VERSION 5.7 ;
  NOWIREEXTENSIONATPIN ON ;
  DIVIDERCHAR "/" ;
  BUSBITCHARS "[]" ;
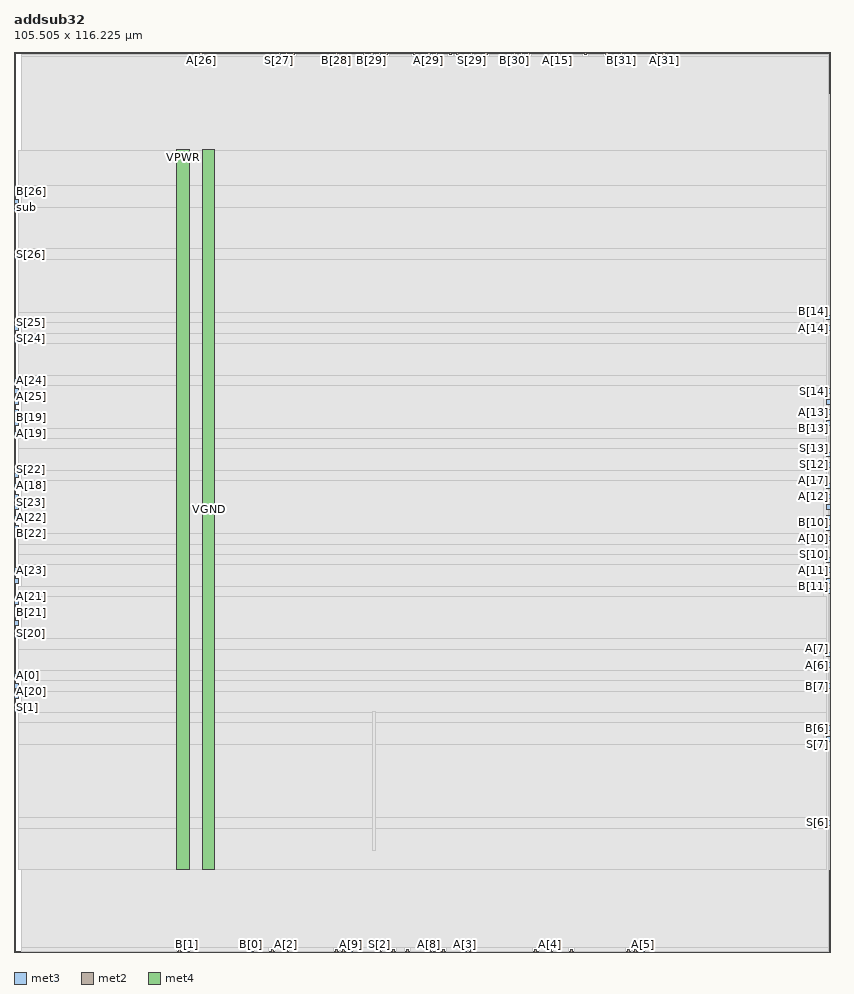
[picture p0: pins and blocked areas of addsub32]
MACRO addsub32
  CLASS BLOCK ;
  FOREIGN addsub32 ;
  ORIGIN 0.000 0.000 ;
  SIZE 105.505 BY 116.225 ;
  PIN A[0]
    DIRECTION INPUT ;
    USE SIGNAL ;
    ANTENNAGATEAREA 0.213000 ;
    PORT
      LAYER met3 ;
        RECT 0.000 35.400 0.600 36.000 ;
    END
  END A[0]
  PIN A[10]
    DIRECTION INPUT ;
    USE SIGNAL ;
    ANTENNAGATEAREA 0.213000 ;
    PORT
      LAYER met3 ;
        RECT 104.905 53.080 105.505 53.680 ;
    END
  END A[10]
  PIN A[11]
    DIRECTION INPUT ;
    USE SIGNAL ;
    ANTENNAGATEAREA 0.213000 ;
    PORT
      LAYER met3 ;
        RECT 104.905 49.000 105.505 49.600 ;
    END
  END A[11]
  PIN A[12]
    DIRECTION INPUT ;
    USE SIGNAL ;
    ANTENNAGATEAREA 0.213000 ;
    PORT
      LAYER met3 ;
        RECT 104.905 58.520 105.505 59.120 ;
    END
  END A[12]
  PIN A[13]
    DIRECTION INPUT ;
    USE SIGNAL ;
    ANTENNAGATEAREA 0.213000 ;
    PORT
      LAYER met3 ;
        RECT 104.905 69.400 105.505 70.000 ;
    END
  END A[13]
  PIN A[14]
    DIRECTION INPUT ;
    USE SIGNAL ;
    ANTENNAGATEAREA 0.213000 ;
    PORT
      LAYER met3 ;
        RECT 104.905 80.280 105.505 80.880 ;
    END
  END A[14]
  PIN A[15]
    DIRECTION INPUT ;
    USE SIGNAL ;
    ANTENNAGATEAREA 0.213000 ;
    PORT
      LAYER met2 ;
        RECT 70.010 115.945 70.290 116.225 ;
    END
  END A[15]
  PIN A[16]
    DIRECTION INPUT ;
    USE SIGNAL ;
    ANTENNAGATEAREA 0.213000 ;
    PORT
      LAYER met2 ;
        RECT 56.210 115.945 56.490 116.225 ;
    END
  END A[16]
  PIN A[17]
    DIRECTION INPUT ;
    USE SIGNAL ;
    ANTENNAGATEAREA 0.213000 ;
    PORT
      LAYER met3 ;
        RECT 104.905 59.880 105.505 60.480 ;
    END
  END A[17]
  PIN A[18]
    DIRECTION INPUT ;
    USE SIGNAL ;
    ANTENNAGATEAREA 0.213000 ;
    PORT
      LAYER met3 ;
        RECT 0.000 59.880 0.600 60.480 ;
    END
  END A[18]
  PIN A[19]
    DIRECTION INPUT ;
    USE SIGNAL ;
    ANTENNAGATEAREA 0.213000 ;
    PORT
      LAYER met3 ;
        RECT 0.000 66.680 0.600 67.280 ;
    END
  END A[19]
  PIN A[1]
    DIRECTION INPUT ;
    USE SIGNAL ;
    ANTENNAGATEAREA 0.213000 ;
    PORT
      LAYER met2 ;
        RECT 21.250 0.000 21.530 0.280 ;
    END
  END A[1]
  PIN A[20]
    DIRECTION INPUT ;
    USE SIGNAL ;
    ANTENNAGATEAREA 0.213000 ;
    PORT
      LAYER met3 ;
        RECT 0.000 34.040 0.600 34.640 ;
    END
  END A[20]
  PIN A[21]
    DIRECTION INPUT ;
    USE SIGNAL ;
    ANTENNAGATEAREA 0.213000 ;
    PORT
      LAYER met3 ;
        RECT 0.000 44.920 0.600 45.520 ;
    END
  END A[21]
  PIN A[22]
    DIRECTION INPUT ;
    USE SIGNAL ;
    ANTENNAGATEAREA 0.213000 ;
    PORT
      LAYER met3 ;
        RECT 0.000 55.800 0.600 56.400 ;
    END
  END A[22]
  PIN A[23]
    DIRECTION INPUT ;
    USE SIGNAL ;
    ANTENNAGATEAREA 0.213000 ;
    PORT
      LAYER met3 ;
        RECT 0.000 49.000 0.600 49.600 ;
    END
  END A[23]
  PIN A[24]
    DIRECTION INPUT ;
    USE SIGNAL ;
    ANTENNAGATEAREA 0.213000 ;
    PORT
      LAYER met3 ;
        RECT 0.000 73.480 0.600 74.080 ;
    END
  END A[24]
  PIN A[25]
    DIRECTION INPUT ;
    USE SIGNAL ;
    ANTENNAGATEAREA 0.213000 ;
    PORT
      LAYER met3 ;
        RECT 0.000 72.120 0.600 72.720 ;
    END
  END A[25]
  PIN A[26]
    DIRECTION INPUT ;
    USE SIGNAL ;
    ANTENNAGATEAREA 0.213000 ;
    PORT
      LAYER met2 ;
        RECT 24.010 115.945 24.290 116.225 ;
    END
  END A[26]
  PIN A[27]
    DIRECTION INPUT ;
    USE SIGNAL ;
    ANTENNAGATEAREA 0.213000 ;
    PORT
      LAYER met2 ;
        RECT 35.970 115.945 36.250 116.225 ;
    END
  END A[27]
  PIN A[28]
    DIRECTION INPUT ;
    USE SIGNAL ;
    ANTENNAGATEAREA 0.213000 ;
    PORT
      LAYER met2 ;
        RECT 45.170 115.945 45.450 116.225 ;
    END
  END A[28]
  PIN A[29]
    DIRECTION INPUT ;
    USE SIGNAL ;
    ANTENNAGATEAREA 0.213000 ;
    PORT
      LAYER met2 ;
        RECT 53.450 115.945 53.730 116.225 ;
    END
  END A[29]
  PIN A[2]
    DIRECTION INPUT ;
    USE SIGNAL ;
    ANTENNAGATEAREA 0.213000 ;
    PORT
      LAYER met2 ;
        RECT 35.050 0.000 35.330 0.280 ;
    END
  END A[2]
  PIN A[30]
    DIRECTION INPUT ;
    USE SIGNAL ;
    ANTENNAGATEAREA 0.213000 ;
    PORT
      LAYER met2 ;
        RECT 76.450 115.945 76.730 116.225 ;
    END
  END A[30]
  PIN A[31]
    DIRECTION INPUT ;
    USE SIGNAL ;
    ANTENNAGATEAREA 0.213000 ;
    PORT
      LAYER met2 ;
        RECT 83.810 115.945 84.090 116.225 ;
    END
  END A[31]
  PIN A[3]
    DIRECTION INPUT ;
    USE SIGNAL ;
    ANTENNAGATEAREA 0.213000 ;
    PORT
      LAYER met2 ;
        RECT 58.050 0.000 58.330 0.280 ;
    END
  END A[3]
  PIN A[4]
    DIRECTION INPUT ;
    USE SIGNAL ;
    ANTENNAGATEAREA 0.213000 ;
    PORT
      LAYER met2 ;
        RECT 69.090 0.000 69.370 0.280 ;
    END
  END A[4]
  PIN A[5]
    DIRECTION INPUT ;
    USE SIGNAL ;
    ANTENNAGATEAREA 0.213000 ;
    PORT
      LAYER met2 ;
        RECT 81.050 0.000 81.330 0.280 ;
    END
  END A[5]
  PIN A[6]
    DIRECTION INPUT ;
    USE SIGNAL ;
    ANTENNAGATEAREA 0.213000 ;
    PORT
      LAYER met3 ;
        RECT 104.905 36.760 105.505 37.360 ;
    END
  END A[6]
  PIN A[7]
    DIRECTION INPUT ;
    USE SIGNAL ;
    ANTENNAGATEAREA 0.213000 ;
    PORT
      LAYER met3 ;
        RECT 104.905 38.120 105.505 38.720 ;
    END
  END A[7]
  PIN A[8]
    DIRECTION INPUT ;
    USE SIGNAL ;
    ANTENNAGATEAREA 0.213000 ;
    PORT
      LAYER met2 ;
        RECT 53.450 0.000 53.730 0.280 ;
    END
  END A[8]
  PIN A[9]
    DIRECTION INPUT ;
    USE SIGNAL ;
    ANTENNAGATEAREA 0.213000 ;
    PORT
      LAYER met2 ;
        RECT 43.330 0.000 43.610 0.280 ;
    END
  END A[9]
  PIN B[0]
    DIRECTION INPUT ;
    USE SIGNAL ;
    ANTENNAGATEAREA 0.213000 ;
    PORT
      LAYER met2 ;
        RECT 30.450 0.000 30.730 0.280 ;
    END
  END B[0]
  PIN B[10]
    DIRECTION INPUT ;
    USE SIGNAL ;
    ANTENNAGATEAREA 0.126000 ;
    PORT
      LAYER met3 ;
        RECT 104.905 54.440 105.505 55.040 ;
    END
  END B[10]
  PIN B[11]
    DIRECTION INPUT ;
    USE SIGNAL ;
    ANTENNAGATEAREA 0.213000 ;
    PORT
      LAYER met3 ;
        RECT 104.905 47.640 105.505 48.240 ;
    END
  END B[11]
  PIN B[12]
    DIRECTION INPUT ;
    USE SIGNAL ;
    ANTENNAGATEAREA 0.213000 ;
    PORT
      LAYER met3 ;
        RECT 104.905 57.160 105.505 57.760 ;
    END
  END B[12]
  PIN B[13]
    DIRECTION INPUT ;
    USE SIGNAL ;
    ANTENNAGATEAREA 0.213000 ;
    PORT
      LAYER met3 ;
        RECT 104.905 68.040 105.505 68.640 ;
    END
  END B[13]
  PIN B[14]
    DIRECTION INPUT ;
    USE SIGNAL ;
    ANTENNAGATEAREA 0.213000 ;
    PORT
      LAYER met3 ;
        RECT 104.905 81.640 105.505 82.240 ;
    END
  END B[14]
  PIN B[15]
    DIRECTION INPUT ;
    USE SIGNAL ;
    ANTENNAGATEAREA 0.213000 ;
    PORT
      LAYER met2 ;
        RECT 66.330 115.945 66.610 116.225 ;
    END
  END B[15]
  PIN B[16]
    DIRECTION INPUT ;
    USE SIGNAL ;
    ANTENNAGATEAREA 0.213000 ;
    PORT
      LAYER met2 ;
        RECT 57.130 115.945 57.410 116.225 ;
    END
  END B[16]
  PIN B[17]
    DIRECTION INPUT ;
    USE SIGNAL ;
    ANTENNAGATEAREA 0.213000 ;
    PORT
      LAYER met3 ;
        RECT 104.905 55.800 105.505 56.400 ;
    END
  END B[17]
  PIN B[18]
    DIRECTION INPUT ;
    USE SIGNAL ;
    ANTENNAGATEAREA 0.213000 ;
    PORT
      LAYER met3 ;
        RECT 0.000 57.160 0.600 57.760 ;
    END
  END B[18]
  PIN B[19]
    DIRECTION INPUT ;
    USE SIGNAL ;
    ANTENNAGATEAREA 0.213000 ;
    PORT
      LAYER met3 ;
        RECT 0.000 68.040 0.600 68.640 ;
    END
  END B[19]
  PIN B[1]
    DIRECTION INPUT ;
    USE SIGNAL ;
    ANTENNAGATEAREA 0.213000 ;
    PORT
      LAYER met2 ;
        RECT 22.170 0.000 22.450 0.280 ;
    END
  END B[1]
  PIN B[20]
    DIRECTION INPUT ;
    USE SIGNAL ;
    ANTENNAGATEAREA 0.213000 ;
    PORT
      LAYER met3 ;
        RECT 0.000 32.680 0.600 33.280 ;
    END
  END B[20]
  PIN B[21]
    DIRECTION INPUT ;
    USE SIGNAL ;
    ANTENNAGATEAREA 0.213000 ;
    PORT
      LAYER met3 ;
        RECT 0.000 43.560 0.600 44.160 ;
    END
  END B[21]
  PIN B[22]
    DIRECTION INPUT ;
    USE SIGNAL ;
    ANTENNAGATEAREA 0.213000 ;
    PORT
      LAYER met3 ;
        RECT 0.000 54.440 0.600 55.040 ;
    END
  END B[22]
  PIN B[23]
    DIRECTION INPUT ;
    USE SIGNAL ;
    ANTENNAGATEAREA 0.213000 ;
    PORT
      LAYER met3 ;
        RECT 0.000 47.640 0.600 48.240 ;
    END
  END B[23]
  PIN B[24]
    DIRECTION INPUT ;
    USE SIGNAL ;
    ANTENNAGATEAREA 0.213000 ;
    PORT
      LAYER met3 ;
        RECT 0.000 69.400 0.600 70.000 ;
    END
  END B[24]
  PIN B[25]
    DIRECTION INPUT ;
    USE SIGNAL ;
    ANTENNAGATEAREA 0.213000 ;
    PORT
      LAYER met3 ;
        RECT 0.000 70.760 0.600 71.360 ;
    END
  END B[25]
  PIN B[26]
    DIRECTION INPUT ;
    USE SIGNAL ;
    ANTENNAGATEAREA 0.213000 ;
    PORT
      LAYER met3 ;
        RECT 0.000 97.960 0.600 98.560 ;
    END
  END B[26]
  PIN B[27]
    DIRECTION INPUT ;
    USE SIGNAL ;
    ANTENNAGATEAREA 0.213000 ;
    PORT
      LAYER met2 ;
        RECT 35.050 115.945 35.330 116.225 ;
    END
  END B[27]
  PIN B[28]
    DIRECTION INPUT ;
    USE SIGNAL ;
    ANTENNAGATEAREA 0.213000 ;
    PORT
      LAYER met2 ;
        RECT 41.490 115.945 41.770 116.225 ;
    END
  END B[28]
  PIN B[29]
    DIRECTION INPUT ;
    USE SIGNAL ;
    ANTENNAGATEAREA 0.213000 ;
    PORT
      LAYER met2 ;
        RECT 46.090 115.945 46.370 116.225 ;
    END
  END B[29]
  PIN B[2]
    DIRECTION INPUT ;
    USE SIGNAL ;
    ANTENNAGATEAREA 0.213000 ;
    PORT
      LAYER met2 ;
        RECT 33.210 0.000 33.490 0.280 ;
    END
  END B[2]
  PIN B[30]
    DIRECTION INPUT ;
    USE SIGNAL ;
    ANTENNAGATEAREA 0.213000 ;
    PORT
      LAYER met2 ;
        RECT 64.490 115.945 64.770 116.225 ;
    END
  END B[30]
  PIN B[31]
    DIRECTION INPUT ;
    USE SIGNAL ;
    ANTENNAGATEAREA 0.213000 ;
    PORT
      LAYER met2 ;
        RECT 78.290 115.945 78.570 116.225 ;
    END
  END B[31]
  PIN B[3]
    DIRECTION INPUT ;
    USE SIGNAL ;
    ANTENNAGATEAREA 0.213000 ;
    PORT
      LAYER met2 ;
        RECT 55.290 0.000 55.570 0.280 ;
    END
  END B[3]
  PIN B[4]
    DIRECTION INPUT ;
    USE SIGNAL ;
    ANTENNAGATEAREA 0.213000 ;
    PORT
      LAYER met2 ;
        RECT 67.250 0.000 67.530 0.280 ;
    END
  END B[4]
  PIN B[5]
    DIRECTION INPUT ;
    USE SIGNAL ;
    ANTENNAGATEAREA 0.213000 ;
    PORT
      LAYER met2 ;
        RECT 80.130 0.000 80.410 0.280 ;
    END
  END B[5]
  PIN B[6]
    DIRECTION INPUT ;
    USE SIGNAL ;
    ANTENNAGATEAREA 0.213000 ;
    PORT
      LAYER met3 ;
        RECT 104.905 28.600 105.505 29.200 ;
    END
  END B[6]
  PIN B[7]
    DIRECTION INPUT ;
    USE SIGNAL ;
    ANTENNAGATEAREA 0.213000 ;
    PORT
      LAYER met3 ;
        RECT 104.905 34.040 105.505 34.640 ;
    END
  END B[7]
  PIN B[8]
    DIRECTION INPUT ;
    USE SIGNAL ;
    ANTENNAGATEAREA 0.213000 ;
    PORT
      LAYER met2 ;
        RECT 50.690 0.000 50.970 0.280 ;
    END
  END B[8]
  PIN B[9]
    DIRECTION INPUT ;
    USE SIGNAL ;
    ANTENNAGATEAREA 0.213000 ;
    PORT
      LAYER met2 ;
        RECT 42.410 0.000 42.690 0.280 ;
    END
  END B[9]
  PIN S[0]
    DIRECTION OUTPUT ;
    USE SIGNAL ;
    ANTENNADIFFAREA 1.336500 ;
    PORT
      LAYER met2 ;
        RECT 41.490 0.000 41.770 0.280 ;
    END
  END S[0]
  PIN S[10]
    DIRECTION OUTPUT ;
    USE SIGNAL ;
    ANTENNADIFFAREA 1.336500 ;
    PORT
      LAYER met3 ;
        RECT 104.905 50.360 105.505 50.960 ;
    END
  END S[10]
  PIN S[11]
    DIRECTION OUTPUT ;
    USE SIGNAL ;
    ANTENNADIFFAREA 0.795200 ;
    PORT
      LAYER met3 ;
        RECT 104.905 46.280 105.505 46.880 ;
    END
  END S[11]
  PIN S[12]
    DIRECTION OUTPUT ;
    USE SIGNAL ;
    ANTENNADIFFAREA 1.336500 ;
    PORT
      LAYER met3 ;
        RECT 104.905 62.600 105.505 63.200 ;
    END
  END S[12]
  PIN S[13]
    DIRECTION OUTPUT ;
    USE SIGNAL ;
    ANTENNADIFFAREA 0.795200 ;
    PORT
      LAYER met3 ;
        RECT 104.905 63.960 105.505 64.560 ;
    END
  END S[13]
  PIN S[14]
    DIRECTION OUTPUT ;
    USE SIGNAL ;
    ANTENNADIFFAREA 1.336500 ;
    PORT
      LAYER met3 ;
        RECT 104.905 72.120 105.505 72.720 ;
    END
  END S[14]
  PIN S[15]
    DIRECTION OUTPUT ;
    USE SIGNAL ;
    ANTENNADIFFAREA 1.336500 ;
    PORT
      LAYER met3 ;
        RECT 104.905 70.760 105.505 71.360 ;
    END
  END S[15]
  PIN S[16]
    DIRECTION OUTPUT ;
    USE SIGNAL ;
    ANTENNADIFFAREA 1.336500 ;
    PORT
      LAYER met2 ;
        RECT 51.610 115.945 51.890 116.225 ;
    END
  END S[16]
  PIN S[17]
    DIRECTION OUTPUT ;
    USE SIGNAL ;
    ANTENNADIFFAREA 1.336500 ;
    PORT
      LAYER met2 ;
        RECT 60.810 115.945 61.090 116.225 ;
    END
  END S[17]
  PIN S[18]
    DIRECTION OUTPUT ;
    USE SIGNAL ;
    ANTENNADIFFAREA 0.795200 ;
    PORT
      LAYER met2 ;
        RECT 54.370 115.945 54.650 116.225 ;
    END
  END S[18]
  PIN S[19]
    DIRECTION OUTPUT ;
    USE SIGNAL ;
    ANTENNADIFFAREA 1.336500 ;
    PORT
      LAYER met2 ;
        RECT 47.010 115.945 47.290 116.225 ;
    END
  END S[19]
  PIN S[1]
    DIRECTION OUTPUT ;
    USE SIGNAL ;
    ANTENNADIFFAREA 1.336500 ;
    PORT
      LAYER met3 ;
        RECT 0.000 31.320 0.600 31.920 ;
    END
  END S[1]
  PIN S[20]
    DIRECTION OUTPUT ;
    USE SIGNAL ;
    ANTENNADIFFAREA 1.336500 ;
    PORT
      LAYER met3 ;
        RECT 0.000 40.840 0.600 41.440 ;
    END
  END S[20]
  PIN S[21]
    DIRECTION OUTPUT ;
    USE SIGNAL ;
    ANTENNADIFFAREA 1.336500 ;
    PORT
      LAYER met3 ;
        RECT 0.000 42.200 0.600 42.800 ;
    END
  END S[21]
  PIN S[22]
    DIRECTION OUTPUT ;
    USE SIGNAL ;
    ANTENNADIFFAREA 1.336500 ;
    PORT
      LAYER met3 ;
        RECT 0.000 61.240 0.600 61.840 ;
    END
  END S[22]
  PIN S[23]
    DIRECTION OUTPUT ;
    USE SIGNAL ;
    ANTENNADIFFAREA 1.336500 ;
    PORT
      LAYER met3 ;
        RECT 0.000 58.520 0.600 59.120 ;
    END
  END S[23]
  PIN S[24]
    DIRECTION OUTPUT ;
    USE SIGNAL ;
    ANTENNADIFFAREA 1.336500 ;
    PORT
      LAYER met3 ;
        RECT 0.000 78.920 0.600 79.520 ;
    END
  END S[24]
  PIN S[25]
    DIRECTION OUTPUT ;
    USE SIGNAL ;
    ANTENNADIFFAREA 1.336500 ;
    PORT
      LAYER met3 ;
        RECT 0.000 80.280 0.600 80.880 ;
    END
  END S[25]
  PIN S[26]
    DIRECTION OUTPUT ;
    USE SIGNAL ;
    ANTENNADIFFAREA 1.336500 ;
    PORT
      LAYER met3 ;
        RECT 0.000 89.800 0.600 90.400 ;
    END
  END S[26]
  PIN S[27]
    DIRECTION OUTPUT ;
    USE SIGNAL ;
    ANTENNADIFFAREA 1.336500 ;
    PORT
      LAYER met2 ;
        RECT 34.130 115.945 34.410 116.225 ;
    END
  END S[27]
  PIN S[28]
    DIRECTION OUTPUT ;
    USE SIGNAL ;
    ANTENNADIFFAREA 1.336500 ;
    PORT
      LAYER met2 ;
        RECT 47.930 115.945 48.210 116.225 ;
    END
  END S[28]
  PIN S[29]
    DIRECTION OUTPUT ;
    USE SIGNAL ;
    ANTENNADIFFAREA 1.336500 ;
    PORT
      LAYER met2 ;
        RECT 58.970 115.945 59.250 116.225 ;
    END
  END S[29]
  PIN S[2]
    DIRECTION OUTPUT ;
    USE SIGNAL ;
    ANTENNADIFFAREA 1.336500 ;
    PORT
      LAYER met2 ;
        RECT 47.010 0.000 47.290 0.280 ;
    END
  END S[2]
  PIN S[30]
    DIRECTION OUTPUT ;
    USE SIGNAL ;
    ANTENNADIFFAREA 1.336500 ;
    PORT
      LAYER met2 ;
        RECT 65.410 115.945 65.690 116.225 ;
    END
  END S[30]
  PIN S[31]
    DIRECTION OUTPUT ;
    USE SIGNAL ;
    ANTENNADIFFAREA 1.336500 ;
    PORT
      LAYER met2 ;
        RECT 73.690 115.945 73.970 116.225 ;
    END
  END S[31]
  PIN S[3]
    DIRECTION OUTPUT ;
    USE SIGNAL ;
    ANTENNADIFFAREA 1.336500 ;
    PORT
      LAYER met2 ;
        RECT 48.850 0.000 49.130 0.280 ;
    END
  END S[3]
  PIN S[4]
    DIRECTION OUTPUT ;
    USE SIGNAL ;
    ANTENNADIFFAREA 0.383400 ;
    PORT
      LAYER met2 ;
        RECT 71.850 0.000 72.130 0.280 ;
    END
  END S[4]
  PIN S[5]
    DIRECTION OUTPUT ;
    USE SIGNAL ;
    ANTENNADIFFAREA 0.795200 ;
    PORT
      LAYER met2 ;
        RECT 79.210 0.000 79.490 0.280 ;
    END
  END S[5]
  PIN S[6]
    DIRECTION OUTPUT ;
    USE SIGNAL ;
    ANTENNADIFFAREA 0.383400 ;
    PORT
      LAYER met3 ;
        RECT 104.905 16.360 105.505 16.960 ;
    END
  END S[6]
  PIN S[7]
    DIRECTION OUTPUT ;
    USE SIGNAL ;
    ANTENNADIFFAREA 1.336500 ;
    PORT
      LAYER met3 ;
        RECT 104.905 27.240 105.505 27.840 ;
    END
  END S[7]
  PIN S[8]
    DIRECTION OUTPUT ;
    USE SIGNAL ;
    ANTENNADIFFAREA 1.336500 ;
    PORT
      LAYER met2 ;
        RECT 58.970 0.000 59.250 0.280 ;
    END
  END S[8]
  PIN S[9]
    DIRECTION OUTPUT ;
    USE SIGNAL ;
    ANTENNADIFFAREA 1.336500 ;
    PORT
      LAYER met2 ;
        RECT 54.370 0.000 54.650 0.280 ;
    END
  END S[9]
  PIN VGND
    DIRECTION INOUT ;
    USE GROUND ;
    PORT
      LAYER met4 ;
        RECT 24.340 10.640 25.940 103.600 ;
    END
  END VGND
  PIN VPWR
    DIRECTION INOUT ;
    USE POWER ;
    PORT
      LAYER met4 ;
        RECT 21.040 10.640 22.640 103.600 ;
    END
  END VPWR
  PIN carryOut
    DIRECTION OUTPUT ;
    USE SIGNAL ;
    ANTENNADIFFAREA 1.336500 ;
    PORT
      LAYER met2 ;
        RECT 82.890 115.945 83.170 116.225 ;
    END
  END carryOut
  PIN sub
    DIRECTION INPUT ;
    USE SIGNAL ;
    ANTENNAGATEAREA 0.742500 ;
    PORT
      LAYER met3 ;
        RECT 0.000 96.600 0.600 97.200 ;
    END
  END sub
  OBS
      LAYER nwell ;
        RECT 5.330 10.795 100.010 103.445 ;
      LAYER li1 ;
        RECT 5.520 10.795 99.820 103.445 ;
      LAYER met1 ;
        RECT 0.990 10.640 105.270 110.800 ;
      LAYER met2 ;
        RECT 1.010 115.665 23.730 115.945 ;
        RECT 24.570 115.665 33.850 115.945 ;
        RECT 34.690 115.665 34.770 115.945 ;
        RECT 35.610 115.665 35.690 115.945 ;
        RECT 36.530 115.665 41.210 115.945 ;
        RECT 42.050 115.665 44.890 115.945 ;
        RECT 45.730 115.665 45.810 115.945 ;
        RECT 46.650 115.665 46.730 115.945 ;
        RECT 47.570 115.665 47.650 115.945 ;
        RECT 48.490 115.665 51.330 115.945 ;
        RECT 52.170 115.665 53.170 115.945 ;
        RECT 54.010 115.665 54.090 115.945 ;
        RECT 54.930 115.665 55.930 115.945 ;
        RECT 56.770 115.665 56.850 115.945 ;
        RECT 57.690 115.665 58.690 115.945 ;
        RECT 59.530 115.665 60.530 115.945 ;
        RECT 61.370 115.665 64.210 115.945 ;
        RECT 65.050 115.665 65.130 115.945 ;
        RECT 65.970 115.665 66.050 115.945 ;
        RECT 66.890 115.665 69.730 115.945 ;
        RECT 70.570 115.665 73.410 115.945 ;
        RECT 74.250 115.665 76.170 115.945 ;
        RECT 77.010 115.665 78.010 115.945 ;
        RECT 78.850 115.665 82.610 115.945 ;
        RECT 83.450 115.665 83.530 115.945 ;
        RECT 84.370 115.665 105.240 115.945 ;
        RECT 1.010 0.560 105.240 115.665 ;
        RECT 1.010 0.070 20.970 0.560 ;
        RECT 21.810 0.070 21.890 0.560 ;
        RECT 22.730 0.070 30.170 0.560 ;
        RECT 31.010 0.070 32.930 0.560 ;
        RECT 33.770 0.070 34.770 0.560 ;
        RECT 35.610 0.070 41.210 0.560 ;
        RECT 42.050 0.070 42.130 0.560 ;
        RECT 42.970 0.070 43.050 0.560 ;
        RECT 43.890 0.070 46.730 0.560 ;
        RECT 47.570 0.070 48.570 0.560 ;
        RECT 49.410 0.070 50.410 0.560 ;
        RECT 51.250 0.070 53.170 0.560 ;
        RECT 54.010 0.070 54.090 0.560 ;
        RECT 54.930 0.070 55.010 0.560 ;
        RECT 55.850 0.070 57.770 0.560 ;
        RECT 58.610 0.070 58.690 0.560 ;
        RECT 59.530 0.070 66.970 0.560 ;
        RECT 67.810 0.070 68.810 0.560 ;
        RECT 69.650 0.070 71.570 0.560 ;
        RECT 72.410 0.070 78.930 0.560 ;
        RECT 79.770 0.070 79.850 0.560 ;
        RECT 80.690 0.070 80.770 0.560 ;
        RECT 81.610 0.070 105.240 0.560 ;
      LAYER met3 ;
        RECT 0.600 98.960 104.905 103.525 ;
        RECT 1.000 96.200 104.905 98.960 ;
        RECT 0.600 90.800 104.905 96.200 ;
        RECT 1.000 89.400 104.905 90.800 ;
        RECT 0.600 82.640 104.905 89.400 ;
        RECT 0.600 81.280 104.505 82.640 ;
        RECT 1.000 79.880 104.505 81.280 ;
        RECT 1.000 78.520 104.905 79.880 ;
        RECT 0.600 74.480 104.905 78.520 ;
        RECT 1.000 73.120 104.905 74.480 ;
        RECT 1.000 67.640 104.505 73.120 ;
        RECT 1.000 66.280 104.905 67.640 ;
        RECT 0.600 64.960 104.905 66.280 ;
        RECT 0.600 62.240 104.505 64.960 ;
        RECT 1.000 62.200 104.505 62.240 ;
        RECT 1.000 60.880 104.905 62.200 ;
        RECT 1.000 54.040 104.505 60.880 ;
        RECT 0.600 52.680 104.505 54.040 ;
        RECT 0.600 51.360 104.905 52.680 ;
        RECT 0.600 50.000 104.505 51.360 ;
        RECT 1.000 47.240 104.505 50.000 ;
        RECT 0.600 45.920 104.505 47.240 ;
        RECT 1.000 45.880 104.505 45.920 ;
        RECT 1.000 40.440 104.905 45.880 ;
        RECT 0.600 39.120 104.905 40.440 ;
        RECT 0.600 36.400 104.505 39.120 ;
        RECT 1.000 36.360 104.505 36.400 ;
        RECT 1.000 35.040 104.905 36.360 ;
        RECT 1.000 33.640 104.505 35.040 ;
        RECT 1.000 30.920 104.905 33.640 ;
        RECT 0.600 29.600 104.905 30.920 ;
        RECT 0.600 26.840 104.505 29.600 ;
        RECT 0.600 17.360 104.905 26.840 ;
        RECT 0.600 15.960 104.505 17.360 ;
        RECT 0.600 10.715 104.905 15.960 ;
      LAYER met4 ;
        RECT 46.295 13.095 46.625 31.105 ;
  END
END addsub32
END LIBRARY

